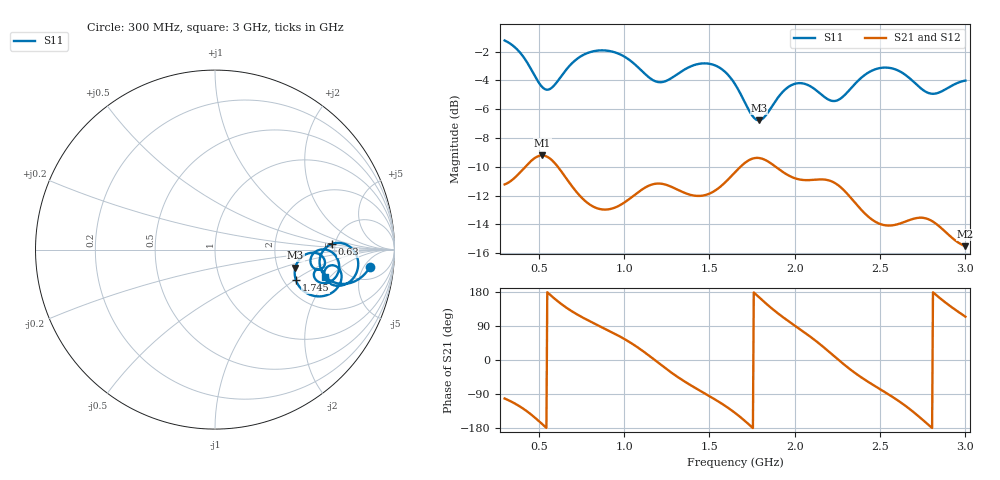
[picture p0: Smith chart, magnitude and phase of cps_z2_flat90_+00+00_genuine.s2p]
! cps_z2_flat90_+00+00_genuine
! simulated by sim/fixtures_fdtd.py (S12 = S21, S22 not computed)
# HZ S RI R 50
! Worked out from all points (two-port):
!   541 points, 300 MHz to 3 GHz, reference 50 ohm
!   highest |S21| = -9.21 dB at 520 MHz (marker M1); lowest = -15.5 dB at 3 GHz (marker M2)
!   |S21| within 3 dB of the highest: start of sweep to 756.9 MHz; 1.034 GHz to 2.333 GHz (1.299 GHz wide, 77.2 % of centre)
!   lowest |S11| = -6.8 dB at 1.79 GHz (marker M3), VSWR 2.69, Z = 125 - j32 ohm
!   |S11| at or under -10 dB: nowhere
!   |S22| runs from - to - dB; largest |S21 - S12| = 0
!   S11 on the Smith chart (normalised r, x): 300 MHz: 9, -7; 630 MHz: 4.67, +0.49; 1.745 GHz: 2.32, -1.03; 3 GHz: 3.46, -1.75
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3e8  0.8634 -0.0968  -0.0549 -0.2691  -0.0549 -0.2691  0 0
4.25e8  0.7144 -0.1915  -0.2185 -0.2311  -0.2185 -0.2311  0 0
5.2e8  0.589 -0.1079  -0.3399 -0.0661  -0.3399 -0.0661  0 0
6.3e8  0.6498 0.0306  -0.2609 0.1601  -0.2609 0.1601  0 0
7.5e8  0.7675 0.00136  -0.1004 0.2262  -0.1004 0.2262  0 0
8.85e8  0.7952 -0.1065  0.0266 0.223  0.0266 0.223  0 0
1.025e9  0.7222 -0.1952  0.1588 0.184  0.1588 0.184  0 0
1.2e9  0.6084 -0.133  0.2744 -0.0342  0.2744 -0.0342  0 0
1.4e9  0.6995 -0.1205  0.0894 -0.2353  0.0894 -0.2353  0 0
1.525e9  0.6824 -0.2125  -0.0539 -0.2539  -0.0539 -0.2539  0 0
1.65e9  0.5553 -0.2587  -0.2301 -0.1964  -0.2301 -0.1964  0 0
1.745e9  0.4508 -0.1704  -0.3353 -0.026  -0.3353 -0.026  0 0
1.79e9  0.4474 -0.1008  -0.3291 0.0826  -0.3291 0.0826  0 0
1.925e9  0.5715 -0.0217  -0.1291 0.2763  -0.1291 0.2763  0 0
2.1e9  0.588 -0.1095  0.1484 0.2428  0.1484 0.2428  0 0
2.26e9  0.5408 -0.0317  0.2713 -0.00464  0.2713 -0.00464  0 0
2.38e9  0.6367 -0.00615  0.1671 -0.1544  0.1671 -0.1544  0 0
2.55e9  0.687 -0.1255  -0.00287 -0.1976  -0.00287 -0.1976  0 0
2.67e9  0.617 -0.1866  -0.1275 -0.1621  -0.1275 -0.1621  0 0
2.78e9  0.5519 -0.1494  -0.2049 -0.0373  -0.2049 -0.0373  0 0
2.885e9  0.5783 -0.1092  -0.1639 0.0907  -0.1639 0.0907  0 0
3e9  0.6115 -0.1524  -0.0692 0.1526  -0.0692 0.1526  0 0
